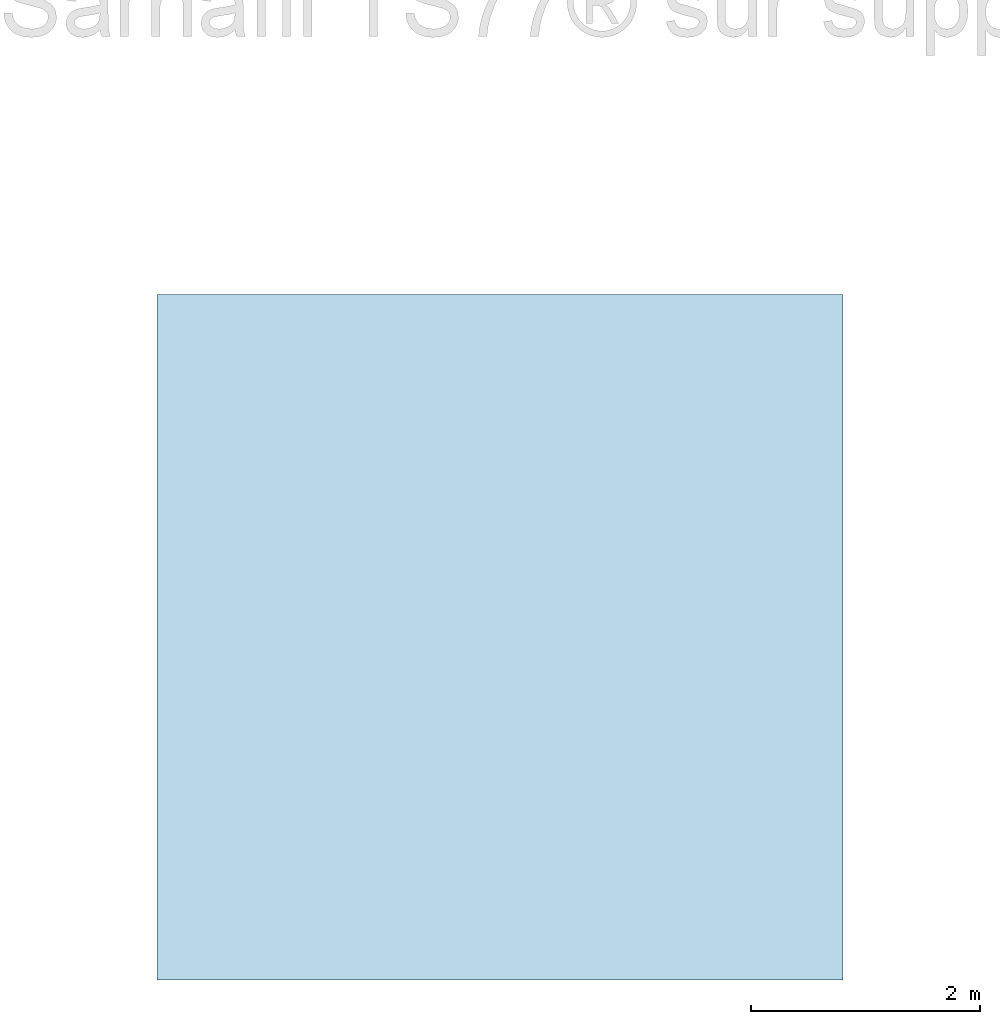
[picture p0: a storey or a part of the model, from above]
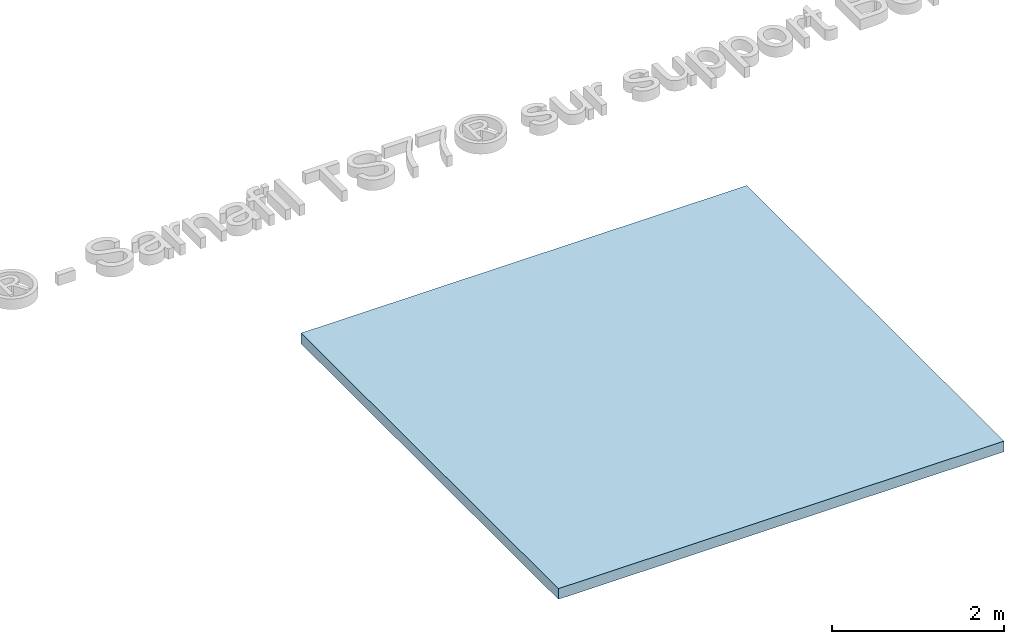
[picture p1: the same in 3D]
Properties of the parts of a building model (IFC2X3)

# File
Description: ViewDefinition [CoordinationView]
File name: Project Number
Time: 2018-02-01T16:29:58
Written by: The EXPRESS Data Manager Version 5.02.0100.07 : 28 Aug 2013
Made in: 20140606_1530(x64) - Exporter 2015.0.2014.0606 - Default UI
Comment: STEP Physical File produced by: The EXPRESS Data Manager Version 5.02.0100.07 : 28 Aug 2013 * Module: EDMstepFileFactory/EDMstandAlone * Creation date: Thu Feb 01 16:29:58 2018 * Host: Polantis_Production_E * Database: C:\Users\ADMINI~1\AppData\Local\Temp\{73AFA2EE-8CA2-4963-B935-4C22D06F0A7B}\ifc * Database version: 5507 * Database creation date: Thu Feb 01 16:29:50 2018 * Schema: IFC2X3 * Model: DataRepository.ifc * Model creation date: Thu Feb 01 16:29:51 2018 * Header model: DataRepository.ifc_HeaderModel * Header model creation date: Thu Feb 01 16:29:51 2018 * EDMuser: sdai-user * EDMgroup: sdai-group * License ID and type: 5605 : Permanent license. Expiry date: * EDMstepFileFactory options: 020000

# IfcProject, Project Number
LongName: Project Name; Phase: Project Status

# IfcSite, Default
RefLatitude: 42, 21, 30, 344238; RefLongitude: -71, -3, -35, -194702; RefElevation: 0 mm
Other - Category: Project Information; Client Name: Owner; Project Address: Enter address here; Project Issue Date: Issue Date; Project Name: Project Name; Project Number: Project Number; Project Status: Project Status

# IfcBuilding
Pset_BuildingCommon - NumberOfStoreys: 1
Other - Category: Project Information; Client Name: Owner; Project Address: Enter address here; Project Issue Date: Issue Date; Project Name: Project Name; Project Number: Project Number; Project Status: Project Status

# IfcBuildingStorey, Level 1
LongName: Level 1; Elevation: 0 mm
Other - Category: Levels; Family Name: Level; Family: Level: 8mm Head; Family and Type: Level: 8mm Head; Type: Level: 8mm Head; Type Id: Level: 8mm Head
Constraints - Elevation: 0 mm; Elevation Base: Project Base Point
Dimensions - Computation Height: 0 mm
Identity Data - Building Story: yes; Name: Level 1; Structural: no; Type Name: 8mm Head
Graphics - Color: 0; Line Pattern: Centre; Line Weight: 1; Symbol: M_Level Head - Circle: M_Level Head - Circle; Symbol at End 1 Default: no; Symbol at End 2 Default: yes

# IfcBuildingElementProxy: Model Text:600mm Arial
In: Level 1
Pset_BuildingElementProxyCommon - Reference: 600mm Arial
Constraints - Work Plane: Level : Level 1
Dimensions - Depth: 150 mm
Graphics - Horizontal Align: Left; Text: Sika® - Sarnafil TS77® sur support Bois
Identity Data - Subcategory: Generic Models; Type Name: 600mm Arial
Other - Category: Generic Models; Family: Model Text: 600mm Arial; Family and Type: Model Text: 600mm Arial; Type: Model Text: 600mm Arial; Type Id: Model Text: 600mm Arial; Family Name: Model Text
Phasing - Phase Created: New Construction
Text - Bold: no; Italic: no; Text Font: Arial; Text Size: 600 mm

# IfcRoof: Basic Roof:Sika® - Sarnafil TS77® sur support Bois, Basic Roof:Sika® - Sarnafil TS77® sur support Bois:130142
In: Level 1
Pset_RoofCommon - Reference: Sika® - Sarnafil TS77® sur support Bois; IsExternal: yes; TotalArea: 36 m2; ProjectedArea: 36 m2
Pset_ManufacturerTypeInformation - Manufacturer: Sika
Constraints - Base Level: Level: Level 1; Base Offset From Level: 0 mm; Cutoff Offset: 0 mm; Related to Mass: no; Room Bounding: yes
Construction - Fascia Depth: 0 mm; Maximum Ridge Height: 152 mm; Rafter Cut: Plumb Cut; Default Thickness: 152 mm
Dimensions - Area: 36 m2; Thickness: 152 mm; Volume: 5.472 m3
Other - Category: Roofs; Family: Basic Roof: Sika® - Sarnafil TS77® sur support Bois; Family and Type: Basic Roof: Sika® - Sarnafil TS77® sur support Bois; Type: Basic Roof: Sika® - Sarnafil TS77® sur support Bois; Type Id: Basic Roof: Sika® - Sarnafil TS77® sur support Bois; Family Name: Basic Roof
Phasing - Phase Created: New Construction
Analytical Properties - Absorptance: 0.1; Heat Transfer Coefficient (U): 2.4; Roughness: 1; Thermal mass: 4712; Thermal Resistance (R): 0.416667
Graphics - Coarse Scale Fill Color: 0
Identity Data - Description: Références : http://fra.sika.com/dms/getdocument.get/5e58ebe6-6e03-3177-87e0-f492d1ccd223/fr_references_sarnafil.pdf Bilan écologique : http://fra.sika.com/dms/getdocument.get/d6e9e23c-972c-3ad4-bca0-0746c801376b/fr_bilan_ecologique_sarnafil_t.pdf Rapport de durabilité : http://fra.sika.com/dms/getdocument.get/de8e9704-825f-3a23-9133-be42ad0ae23e/fr_rapport_durabilite_membrane_sarnafil_t.pdf Brochure : http://fra.sika.com/dms/getdocument.get/8d53d241-2375-3598-94c8-274db6ff9b48/fr_systemes_etancheite_toitures_sarnafil.pdf; Manufacturer: Sika; Model: Sarnafil TS77® sur support Bois; Type Comments: Sarnafil TS77® sur support Bois; Type Name: Sika® - Sarnafil TS77® sur support Bois; URL: http://fra.sika.com/dms/getdocument.get/3e0f241c-a448-302e-a8ab-d61880cdf3a7/fr_descriptifs_types_systeme_par_fixation_mecanique.pdf

# IfcSlab: Basic Roof:Sika® - Sarnafil TS77® sur support Bois, Basic Roof:Sika® - Sarnafil TS77® sur support Bois:130142
In: Level 1
PredefinedType: ROOF; Material: Sika - Sarnafil® TS 77-20 2 mm, Isolation thermique - Laine de roche 100 mm, Bois 50 mm
Pset_SlabCommon - Reference: Sika® - Sarnafil TS77® sur support Bois; IsExternal: yes; LoadBearing: yes; ThermalTransmittance: 2.4 kg/K/s3; PitchAngle: 0 deg
Pset_ManufacturerTypeInformation - Manufacturer: Sika
